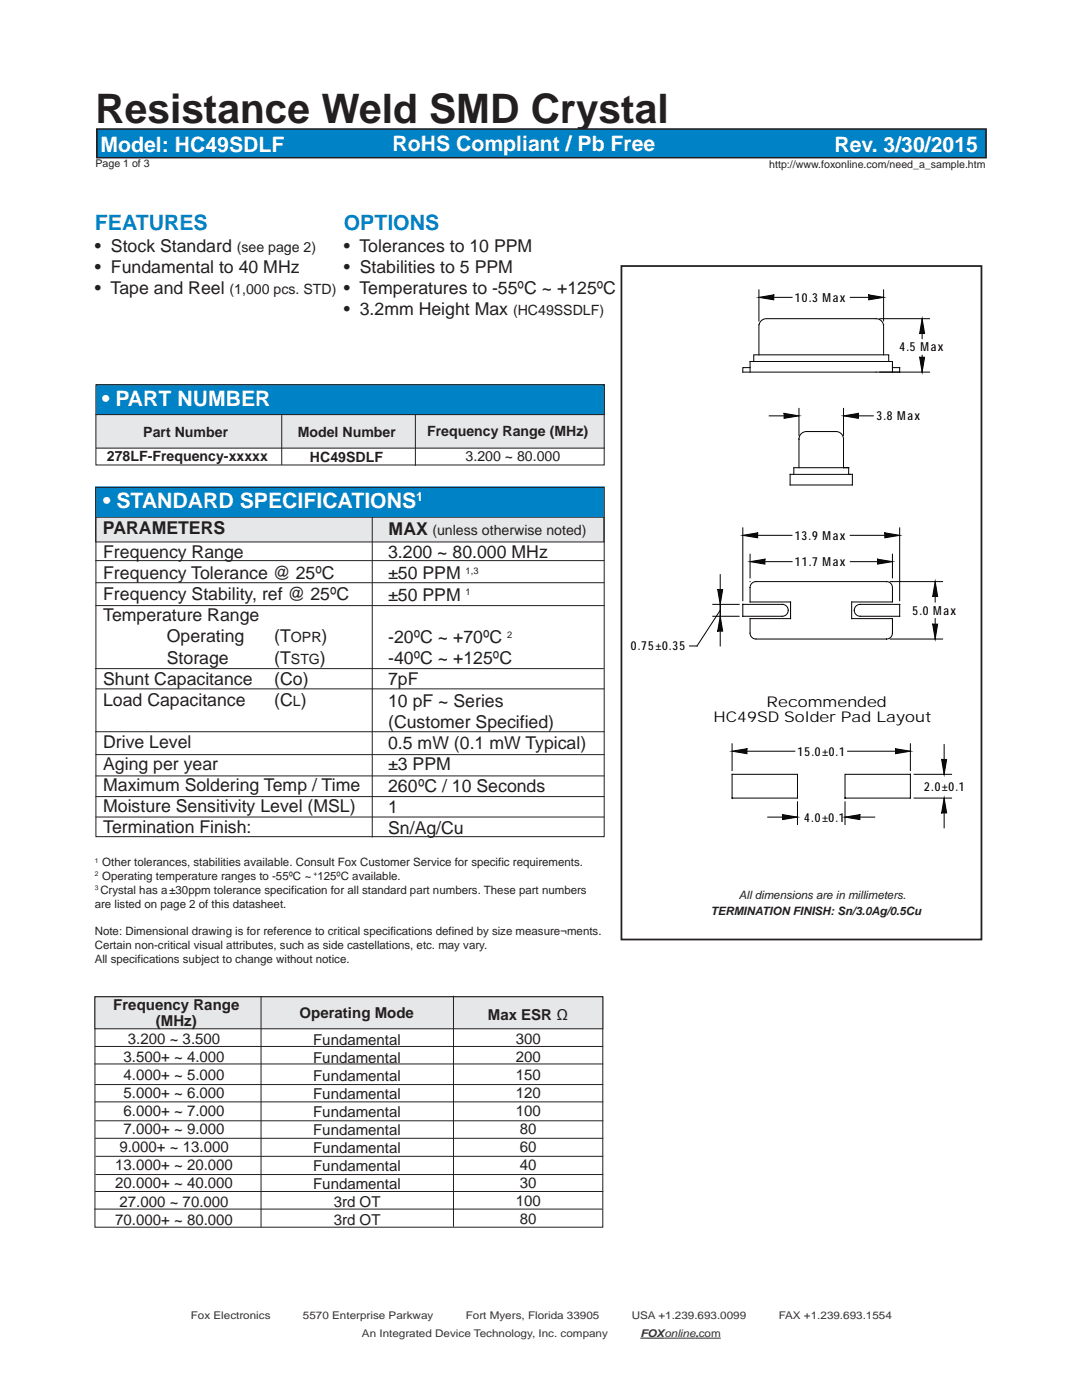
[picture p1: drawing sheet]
<svg xmlns="http://www.w3.org/2000/svg" width="216mm" height="279mm" viewBox="0 0 216 279" stroke-linecap="round" stroke-linejoin="round" font-family="sans-serif">
<defs><g id="words">
<text font-size="8.1" fill="#231f20" x="19" y="24.6">Resistance Weld SMD Crystal</text>
<g font-size="4.2" fill="#fff">
<text x="20.1" y="30.3">Model: HC49SDLF</text>
<text x="78.3" y="30.1">RoHS Compliant / Pb Free</text>
<text x="166.5" y="30.4">Rev. 3/30/2015</text>
<text x="20.4" y="81">• PART NUMBER</text>
<text x="20.6" y="101.3">• STANDARD SPECIFICATIONS</text>
</g>
<g font-size="4.2" fill="#0083c6">
<text x="18.9" y="46">FEATURES</text>
<text x="68.6" y="46">OPTIONS</text>
</g>
<g font-size="3.5" fill="#231f20">
<text x="18.9" y="50.2">• Stock Standard</text>
<text x="68.6" y="50.2">• Tolerances to 10 PPM</text>
<text x="18.9" y="54.4">• Fundamental to 40 MHz</text>
<text x="18.9" y="58.7">• Tape and Reel</text>
<text x="68.6" y="54.4">• Stabilities to 5 PPM</text>
<text x="68.6" y="58.7">• Temperatures to -55ºC ~ +125ºC</text>
<text x="68.6" y="62.9">• 3.2mm Height Max</text>
<text x="20.5" y="106.7">PARAMETERS</text>
<text x="77.6" y="106.8">MAX</text>
<text x="20.6" y="111.3">Frequency Range</text>
<text x="77.5" y="111.4">3.200 ~ 80.000 MHz</text>
<text x="20.6" y="115.5">Frequency Tolerance @ 25ºC</text>
<text x="20.6" y="119.7">Frequency Stability, ref @ 25ºC</text>
<text x="77.5" y="115.6">±50 PPM</text>
<text x="77.5" y="119.9">±50 PPM</text>
<text x="20.6" y="124">Temperature Range</text>
<text x="33.3" y="128.2">Operating</text>
<text x="54.7" y="128.2">(T</text>
<text x="64.2" y="128.2">)</text>
<text x="77.5" y="128.3">-20ºC ~ +70ºC</text>
<text x="20.6" y="136.7">Shunt Capacitance</text>
<text x="33.3" y="132.4">Storage</text>
<text x="54.7" y="132.4">(T</text>
<text x="54.7" y="136.7">(Co)</text>
<text x="63.8" y="132.4">)</text>
<text x="77.5" y="132.6">-40ºC ~ +125ºC</text>
<text x="77.5" y="136.8">7pF</text>
<text x="20.6" y="140.9">Load Capacitance</text>
<text x="54.7" y="140.9">(C )</text>
<text x="77.5" y="141">10 pF ~ Series</text>
<text x="20.6" y="149.4">Drive Level</text>
<text x="77.5" y="145.3">(Customer Specified)</text>
<text x="77.5" y="149.5">0.5 mW (0.1 mW Typical)</text>
<text x="20.6" y="153.6">Aging per year</text>
<text x="77.5" y="153.7">±3 PPM</text>
<text x="20.6" y="157.8">Maximum Soldering Temp / Time</text>
<text x="77.5" y="158">260ºC / 10 Seconds</text>
<text x="20.6" y="162.1">Moisture Sensitivity Level (MSL)</text>
<text x="20.6" y="166.3">Termination Finish:</text>
<text x="77.5" y="162.2">1</text>
<text x="77.5" y="166.4">Sn/Ag/Cu</text>
</g>
<g font-size="3">
<text x="153" y="141">Recommended</text>
<text x="142.3" y="144.1">HC49SD Solder Pad Layout</text>
</g>
<g font-size="3" fill="#231f20">
<text x="22.6" y="201.5">Frequency Range</text>
<text x="59.8" y="203.2">Operating Mode</text>
<text x="97.3" y="203.6">Max ESR Ω</text>
<text x="25.5" y="208.4">3.200 ~ 3.500</text>
<text x="31.1" y="204.9">(MHz)</text>
<text x="62.5" y="208.5">Fundamental</text>
<text x="102.9" y="208.4">300</text>
<text x="24.7" y="212">3.500+ ~ 4.000</text>
<text x="24.7" y="215.6">4.000+ ~ 5.000</text>
<text x="62.5" y="212.1">Fundamental</text>
<text x="62.5" y="215.7">Fundamental</text>
<text x="102.9" y="212">200</text>
<text x="102.9" y="215.6">150</text>
<text x="24.7" y="219.2">5.000+ ~ 6.000</text>
<text x="62.5" y="219.3">Fundamental</text>
<text x="102.9" y="219.2">120</text>
<text x="24.7" y="222.8">6.000+ ~ 7.000</text>
<text x="24.7" y="226.4">7.000+ ~ 9.000</text>
<text x="62.5" y="222.9">Fundamental</text>
<text x="62.5" y="226.5">Fundamental</text>
<text x="102.9" y="222.8">100</text>
<text x="103.7" y="226.4">80</text>
<text x="23" y="233.6">13.000+ ~ 20.000</text>
<text x="23.8" y="230">9.000+ ~ 13.000</text>
<text x="62.5" y="230.1">Fundamental</text>
<text x="62.5" y="233.7">Fundamental</text>
<text x="103.7" y="230">60</text>
<text x="103.7" y="233.6">40</text>
<text x="23" y="237.2">20.000+ ~ 40.000</text>
<text x="62.5" y="237.3">Fundamental</text>
<text x="103.7" y="237.2">30</text>
<text x="23" y="244.4">70.000+ ~ 80.000</text>
<text x="23.9" y="240.8">27.000 ~ 70.000</text>
<text x="66.6" y="240.9">3rd OT</text>
<text x="66.6" y="244.5">3rd OT</text>
<text x="102.9" y="240.8">100</text>
<text x="103.7" y="244.3">80</text>
</g>
<g font-size="2.8" fill="#231f20">
<text x="47.2" y="50.2">(see page 2)</text>
<text x="45.8" y="58.7">(1,000 pcs. STD)</text>
<text x="102.4" y="62.9">(HC49SSDLF)</text>
<text x="28.6" y="87.2">Part Number</text>
<text x="59.4" y="87.2">Model Number</text>
<text x="85.2" y="87">Frequency Range (MHz)</text>
<text x="21.3" y="92.1">278LF-Frequency-xxxxx</text>
<text x="61.8" y="92.3">HC49SDLF</text>
<text x="92.9" y="92">3.200 ~ 80.000</text>
<text x="86.3" y="106.8">(unless otherwise noted)</text>
<text x="58" y="128.2">OPR</text>
<text x="58" y="132.4">STG</text>
<text x="58.4" y="140.9">L</text>
</g>
<g font-size="2.5">
<text x="158.6" y="60.2">10.3 Max</text>
<text x="179.5" y="70.1">4.5 Max</text>
<text x="174.9" y="83.9">3.8 Max</text>
<text x="158.6" y="107.7">13.9 Max</text>
<text x="158.6" y="113">11.7 Max</text>
<text x="182.1" y="122.7">5.0 Max</text>
<text x="125.9" y="129.8">0.75±0.35</text>
<text x="159.1" y="150.8">15.0±0.1</text>
<text x="184.4" y="157.8">2.0±0.1</text>
<text x="160.5" y="163.9">4.0±0.1</text>
</g>
<text font-size="2.5" fill="#fff" x="83.1" y="99.9">1</text>
<g font-size="2.3" fill="#231f20">
<text x="20.4" y="172.9">Other tolerances, stabilities available. Consult Fox Customer Service for specific requirements.</text>
<text x="20" y="178.4">Crystal has a±30ppm tolerance specification for all standard part numbers. These part numbers</text>
<text x="20.4" y="175.7">Operating temperature ranges to -55ºC ~ 125ºC available.</text>
<text x="147.4" y="179.4">All dimensions are in millimeters.</text>
<text x="18.9" y="181.2">are listed on page 2 of this datasheet.</text>
<text x="141.8" y="182.6">TERMINATION FINISH: Sn/3.0Ag/0.5Cu</text>
<text x="18.9" y="186.7">Note: Dimensional drawing is for reference to critical specifications defined by size measure¬ments.</text>
<text x="18.9" y="189.4">Certain non-critical visual attributes, such as side castellations, etc. may vary.</text>
<text x="18.9" y="192.2">All specifications subject to change without notice.</text>
</g>
<g font-size="2.1" fill="#231f20">
<text x="19" y="33.4">Page 1 of 3</text>
<text x="153.5" y="33.5">http://www.foxonline.com/need_a_sample.htm</text>
</g>
<g font-size="2.1" fill="#333">
<text x="38.1" y="263.3">Fox Electronics</text>
<text x="60.5" y="263.3">5570 Enterprise Parkway</text>
<text x="92.9" y="263.3">Fort Myers, Florida 33905</text>
<text x="126.1" y="263.3">USA +1.239.693.0099</text>
<text x="155.4" y="263.3">FAX +1.239.693.1554</text>
<text x="72.2" y="266.8">An Integrated Device Technology, Inc. company</text>
<text x="127.8" y="266.8">FOXonline.com</text>
</g>
<g font-size="1.9" fill="#231f20">
<text x="92.9" y="114.6">1,3</text>
<text x="92.9" y="118.8">1</text>
<text x="101.2" y="127.3">2</text>
</g>
<g font-size="1.3" fill="#231f20">
<text x="18.9" y="172.2">1</text>
<text x="18.9" y="174.9">2</text>
<text x="18.9" y="177.7">3</text>
<text x="62.6" y="174.9">+</text>
</g>
</g></defs>
<path d="M127.8 267.1h4.8M138.8 267.1h.6" fill="none" stroke="#333" stroke-width=".22"/>
<path d="M132.6 267.1h6.2M139.4 267.1h4.4" fill="none" stroke="#333" stroke-width=".2"/>
<path d="M19.1 76.8h101.5v6h-101.5z" fill-rule="evenodd" fill="#0083c6"/>
<path d="M19 82.8h101.6v6.7h-101.6z" fill-rule="evenodd" fill="#e6e7e9"/>
<path d="M19.1 76.8h101.5v16h-101.5zM19 82.7h101.6M19.2 89.4h101.5M56.2 82.8v10M82.9 82.8v10.2" fill="none" stroke="#231f20" stroke-width=".2"/>
<path d="M19.3 25.8h177.5v5.7h-177.5z" fill-rule="evenodd" fill="#0083c6"/>
<path d="M19.3 25.8h177.5v5.7h-177.5z" fill="none" stroke="#231f20" stroke-width=".32"/>
<path d="M124 53.1h71.8v134.4h-71.8z" fill="none" stroke="#231f20" stroke-width=".35"/>
<path d="M125.5 54.6h69v112.3h-69z" fill-rule="evenodd" fill="#fff"/>
<g fill="none" stroke="#000" stroke-width=".2">
<path d="M151.4 57.9v6.2M151.4 59.3l3-.5v1zM154.4 59.3h3.7M169.7 59.3h3.6M173.3 58.8l3 .5-3 .5zM176.3 57.9v6.2M176.3 59.3h.1M149.7 73.4h-1.5v.9h37.3M149.7 74.3v-2.2h28.4v2.2M150.4 72.1v-1.3h26.9v1.3M151.4 64.8h.1M151.4 70.8v-5.7a1.5 1.5 0 0 1 1.5-1.5h21.9a1.5 1.5 0 0 1 1.5 1.5v5.7"/>
<path d="M174.8 63.6h.1M175.5 63.6h10M176.3 64.8h.1M178.1 73.4h1.4v.9M183.5 71.3h1l-.5 3zM184 63.6l.5 3h-1zM184 66.6v1M184 70.9v.4M153.5 83h3M156.5 82.5l2.9 .5-2.9 .5zM157.7 94.7h12.4v2.1h-12.4zM159.4 81.5v5.4"/>
<path d="M159.4 87.6v5.7M159.4 87.6h.1M159.4 87.6a1.5 1.5 0 0 1 1.5-1.5h5.9a1.5 1.5 0 0 1 1.5 1.5M168.3 83l3-.5v1zM168.3 81.5v5.4M168.3 87.6v5.7M168.3 83h.1M168.3 87.6h.1M169.3 94.7v-1.4h-10.9v1.4M171.3 83h2.9M143.2 117.7h1l-.5 2.9zM143.7 114.7v3"/>
<path d="M148.2 106.8l3-.5v1zM148.2 105.4v14.5M149.7 110.6v4.7M149.7 116.1h.1M149.7 112.1l2.9-.5v1zM151.2 106.8h6.8M152.6 112.1h5.5M169.6 106.8h7M169.7 112.1h5.4M175.1 111.6l3 .5-3 .5zM176.6 106.3l2.9 .5-2.9 .5zM177.6 116.1h10.5"/>
<path d="M178.1 110.6v4.7M178.1 112.1h.1M179.5 105.4v14.5M179.5 106.8h.1M186.6 116.1l.5 2.9h-1zM186.6 119v1.1M142.2 120.6h5.3M142.2 123h5.3M143.7 123l.5 3h-1zM143.7 120.6v2.4M143.7 126v2.9M143.7 121.8l-4.6 7.1h-1.5"/>
<path d="M148.2 120.6h7.9a1.19 1.19 0 0 1 1.2 1.2 1.19 1.19 0 0 1-1.2 1.2h-7.9zM157.3 121.8h.1M170.5 121.8h.1M170.9 120.9l.7-.3h7.9v2.4h-7.9a1.19 1.19 0 0 1-1.1-.8 1.19 1.19 0 0 1 .4-1.3zM177.6 127.5h10.5M178 120.1h-8.1v3.4h8.1M178.1 120.1v-2.8a1.19 1.19 0 0 0-1.2-1.2h-26.1a1.18 1.18 0 0 0-1.1 1.2v2.8h8.1v3.4h-8.1v2.8a1.18 1.18 0 0 0 1.1 1.2h26.1a1.19 1.19 0 0 0 1.2-1.2v-2.8M186.1 124.6h1l-.5 2.9zM186.6 123.4v1.2M146.1 154.5h13v4.8h-13zM146.1 154.5h.1M146.1 148.4v5.4"/>
<path d="M146.1 149.9l2.9-.5v1zM149 149.9h9.6M159.1 159.3h.1M168.6 154.5h13.1v4.8h-13.1zM168.6 159.3h.1M169.1 149.9h9.6M178.7 149.4l3 .5-3 .5zM181.7 159.3h.1M181.7 154.5h.1M181.7 148.4v5.4M181.7 149.9h.1M182.4 159.3h7.5"/>
<path d="M182.4 154.5h7.5M187.9 151.6h1l-.5 2.9zM188.4 159.3l.5 2.9h-1zM188.4 148.6v3M153.2 163.1h3M156.2 162.6l2.9 .5-2.9 .5zM159.1 160v4.6M168.6 163.1l3-.5v1zM168.6 160v4.6M168.6 163.1h.1M171.6 163.1h2.9M188.4 162.2v3"/>
</g>
<g fill="#000">
<path d="M151.4 59.3l3-.5v1zM173.3 58.8l3 .5-3 .5zM184 63.6l.5 3h-1zM183.5 71.3h1l-.5 3zM156.5 82.5l2.9 .5-2.9 .5zM168.3 83l3-.5v1zM143.2 117.7h1l-.5 2.9zM148.2 106.8l3-.5v1zM149.7 112.1l2.9-.5v1zM175.1 111.6l3 .5-3 .5zM176.6 106.3l2.9 .5-2.9 .5zM186.6 116.1l.5 2.9h-1z"/>
<path d="M143.7 123l.5 3h-1zM186.1 124.6h1l-.5 2.9zM146.1 149.9l2.9-.5v1zM178.7 149.4l3 .5-3 .5zM187.9 151.6h1l-.5 2.9zM156.2 162.6l2.9 .5-2.9 .5zM168.6 163.1l3-.5v1zM188.4 159.3l.5 2.9h-1z"/>
</g>
<path d="M19.1 103.2h101.4v5h-101.4z" fill-rule="evenodd" fill="#e6e7e9"/>
<path d="M19 111.9h101.6M19.1 116.3h101.5M19.1 103.2h101.4v5h-101.4zM74.3 102.7v64.4M19.1 137.5h101.5M19 146h101.6M19.1 150.6h101.5" fill="none" stroke="#231f20" stroke-width=".2"/>
<path d="M19.1 97.2h101.4v5.8h-101.4z" fill-rule="evenodd" fill="#0083c6"/>
<path d="M19.1 97.2h101.4v5.8h-101.4z" fill="none" stroke="#0083c6" stroke-width=".2"/>
<path d="M19.1 97.3h101.5v69.7h-101.5zM18.9 133.4h101.6M19 120.9h101.6M19 154.9h101.6M19 159h101.6M19 163.1h101.6M18.9 198.9h101.4v46h-101.4z" fill="none" stroke="#231f20" stroke-width=".2"/>
<path d="M18.9 198.9h101.4v6.4h-101.4z" fill-rule="evenodd" fill="#e6e7e9"/>
<g fill="none" stroke="#231f20" stroke-width=".2">
<path d="M18.9 198.9h101.4v6.4h-101.4zM52.1 198.8v46.1M90.5 198.7v46.1M18.9 212.3h101.5M18.9 208.8h101.5M18.9 219.9h101.5M19 216.4h101.4M19 227.2h101.4M19 237.8h101.4M19 223.7h101.4M19 234.4h101.4M19.1 230.8h101.3"/>
<path d="M18.8 241.3h101.4"/>
</g>
<use href="#words"/>
</svg>
